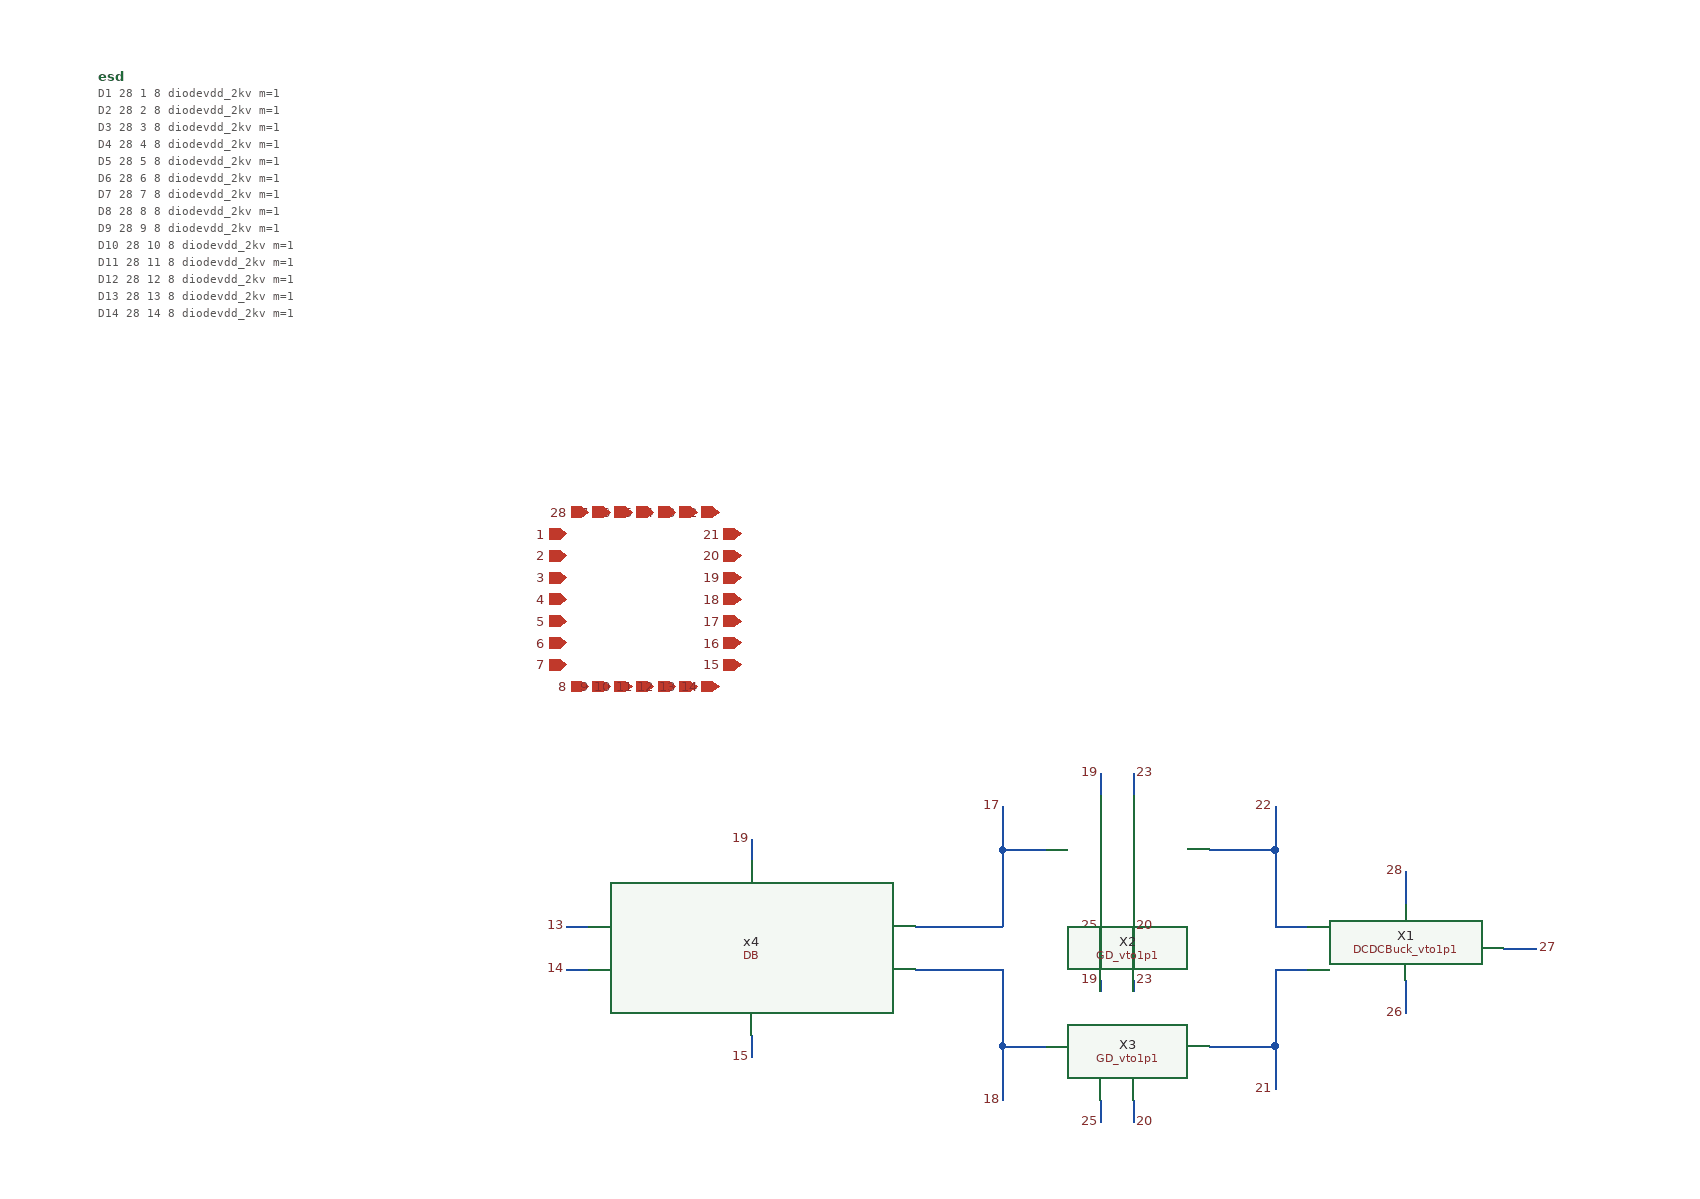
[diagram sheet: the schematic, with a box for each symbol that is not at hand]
v {xschem version=3.4.5 file_version=1.2
}
G {}
K {}
V {}
S {}
E {}
N -70 240 -70 260 {
lab=15}
N -70 60 -70 80 {
lab=19}
N 80 140 160 140 {
lab=17}
N 80 180 160 180 {
lab=18}
N -240 140 -220 140 {
lab=13}
N -240 180 -220 180 {
lab=14}
N 410 30 410 70 {
lab=22}
N 410 250 410 290 {
lab=21}
N 350 70 410 70 {
lab=22}
N 350 250 410 250 {
lab=21}
N 410 140 440 140 {
lab=22}
N 410 70 410 140 {
lab=22}
N 410 180 440 180 {
lab=21}
N 410 180 410 250 {
lab=21}
N 250 300 250 320 {
lab=25}
N 250 120 250 140 {
lab=25}
N 530 90 530 120 {
lab=28}
N 620 160 650 160 {
lab=27}
N 530 190 530 220 {
lab=26}
N 160 180 160 250 {
lab=18}
N 160 70 160 140 {
lab=17}
N 160 70 200 70 {
lab=17}
N 160 250 200 250 {
lab=18}
N 280 190 280 200 {
lab=23}
N 280 300 280 320 {
lab=20}
N 280 120 280 140 {
lab=20}
N 250 190 250 200 {
lab=19}
N 250 0 250 20 {
lab=19}
N 280 0 280 20 {
lab=23}
N 160 30 160 70 {
lab=17}
N 160 250 160 300 {
lab=18}
C {iopin.sym} -240 -220 2 0 {name=p8 lab=1}
C {iopin.sym} -240 -200 2 0 {name=p9 lab=2}
C {iopin.sym} -240 -180 2 0 {name=p10 lab=3}
C {iopin.sym} -240 -160 2 0 {name=p11 lab=4}
C {iopin.sym} -240 -140 2 0 {name=p12 lab=5}
C {iopin.sym} -240 -120 2 0 {name=p13 lab=6}
C {iopin.sym} -240 -100 2 0 {name=p14 lab=7}
C {iopin.sym} -220 -80 1 0 {name=p15 lab=8}
C {iopin.sym} -200 -80 1 0 {name=p16 lab=9}
C {iopin.sym} -180 -80 1 0 {name=p17 lab=10}
C {iopin.sym} -160 -80 1 0 {name=p18 lab=11}
C {iopin.sym} -140 -80 1 0 {name=p19 lab=12}
C {iopin.sym} -120 -80 1 0 {name=p20 lab=13}
C {iopin.sym} -100 -80 1 0 {name=p21 lab=14}
C {iopin.sym} -80 -100 0 0 {name=p22 lab=15}
C {iopin.sym} -80 -120 0 0 {name=p23 lab=16}
C {iopin.sym} -80 -140 0 0 {name=p24 lab=17}
C {iopin.sym} -80 -160 0 0 {name=p25 lab=18}
C {iopin.sym} -80 -180 0 0 {name=p26 lab=19}
C {iopin.sym} -80 -200 0 0 {name=p27 lab=20}
C {iopin.sym} -80 -220 0 0 {name=p28 lab=21}
C {iopin.sym} -100 -240 3 0 {name=p29 lab=22}
C {iopin.sym} -120 -240 3 0 {name=p30 lab=23}
C {iopin.sym} -140 -240 3 0 {name=p31 lab=24}
C {iopin.sym} -160 -240 3 0 {name=p32 lab=25}
C {iopin.sym} -180 -240 3 0 {name=p33 lab=26}
C {iopin.sym} -200 -240 3 0 {name=p34 lab=27}
C {iopin.sym} -220 -240 3 0 {name=p35 lab=28}
C {lab_pin.sym} -70 60 1 0 {name=p3 sig_type=std_logic lab=19}
C {code_shown.sym} -670 -640 0 0 {name=esd only_toplevel=false spice_ignore=true value="
D1 28 1 8 diodevdd_2kv m=1
D2 28 2 8 diodevdd_2kv m=1
D3 28 3 8 diodevdd_2kv m=1
D4 28 4 8 diodevdd_2kv m=1
D5 28 5 8 diodevdd_2kv m=1
D6 28 6 8 diodevdd_2kv m=1
D7 28 7 8 diodevdd_2kv m=1
D8 28 8 8 diodevdd_2kv m=1
D9 28 9 8 diodevdd_2kv m=1
D10 28 10 8 diodevdd_2kv m=1
D11 28 11 8 diodevdd_2kv m=1
D12 28 12 8 diodevdd_2kv m=1
D13 28 13 8 diodevdd_2kv m=1
D14 28 14 8 diodevdd_2kv m=1
D15 28 15 8 diodevdd_2kv m=1
D16 28 16 8 diodevdd_2kv m=1
D17 28 17 8 diodevdd_2kv m=1
D18 28 18 8 diodevdd_2kv m=1
D19 28 19 8 diodevdd_2kv m=1
D20 28 20 8 diodevdd_2kv m=1
D21 28 21 8 diodevdd_2kv m=1
D22 28 22 8 diodevdd_2kv m=1
D23 28 23 8 diodevdd_2kv m=1
D24 28 24 8 diodevdd_2kv m=1
D25 28 25 8 diodevdd_2kv m=1
D26 28 26 8 diodevdd_2kv m=1
D27 28 27 8 diodevdd_2kv m=1
D28 28 28 8 diodevdd_2kv m=1

D29 28 1 8 diodevss_2kv m=1
D30 28 2 8 diodevss_2kv m=1
D31 28 3 8 diodevss_2kv m=1
D32 28 4 8 diodevss_2kv m=1
D33 28 5 8 diodevss_2kv m=1
D34 28 6 8 diodevss_2kv m=1
D35 28 7 8 diodevss_2kv m=1
D36 28 8 8 diodevss_2kv m=1
D37 28 9 8 diodevss_2kv m=1
D38 28 10 8 diodevss_2kv m=1
D39 28 11 8 diodevss_2kv m=1
D40 28 12 8 diodevss_2kv m=1
D41 28 13 8 diodevss_2kv m=1
D42 28 14 8 diodevss_2kv m=1
D43 28 15 8 diodevss_2kv m=1
D44 28 16 8 diodevss_2kv m=1
D45 28 17 8 diodevss_2kv m=1
D46 28 18 8 diodevss_2kv m=1
D47 28 19 8 diodevss_2kv m=1
D48 28 20 8 diodevss_2kv m=1
D49 28 21 8 diodevss_2kv m=1
D50 28 22 8 diodevss_2kv m=1
D51 28 23 8 diodevss_2kv m=1
D52 28 24 8 diodevss_2kv m=1
D53 28 25 8 diodevss_2kv m=1
D54 28 26 8 diodevss_2kv m=1
D55 28 27 8 diodevss_2kv m=1
D56 28 28 8 diodevss_2kv m=1
"}
C {lab_pin.sym} -240 140 0 0 {name=p38 sig_type=std_logic lab=13}
C {lab_pin.sym} -240 180 0 0 {name=p39 sig_type=std_logic lab=14}
C {lab_pin.sym} -70 260 3 0 {name=p1 sig_type=std_logic lab=15}
C {lab_pin.sym} 410 30 0 0 {name=p2 sig_type=std_logic lab=22}
C {lab_pin.sym} 410 290 0 0 {name=p4 sig_type=std_logic lab=21}
C {lab_pin.sym} 250 320 0 0 {name=p5 sig_type=std_logic lab=25}
C {lab_pin.sym} 280 0 2 0 {name=p6 sig_type=std_logic lab=23}
C {lab_pin.sym} 280 190 2 0 {name=p7 sig_type=std_logic lab=23
}
C {lab_pin.sym} 530 90 0 0 {name=p36 sig_type=std_logic lab=28}
C {lab_pin.sym} 530 220 0 0 {name=p37 sig_type=std_logic lab=26}
C {lab_pin.sym} 250 140 0 0 {name=p40 sig_type=std_logic lab=25}
C {lab_pin.sym} 650 160 2 0 {name=p41 sig_type=std_logic lab=27}
C {../Digital_Block/DB.sym} -70 160 0 0 {name=x4}
C {../GD/GD_vto1p1.sym} 230 110 0 0 {name=X2}
C {../GD/GD_vto1p1.sym} 230 290 0 0 {name=X3}
C {../DCDCBuck/DCDCBuck_vto1p1.sym} 540 180 0 0 {name=X1}
C {lab_pin.sym} 280 140 0 1 {name=p42 sig_type=std_logic lab=20
}
C {lab_pin.sym} 280 320 0 1 {name=p43 sig_type=std_logic lab=20}
C {lab_pin.sym} 250 190 0 0 {name=p44 sig_type=std_logic lab=19}
C {lab_pin.sym} 250 0 0 0 {name=p45 sig_type=std_logic lab=19}
C {lab_pin.sym} 160 30 0 0 {name=p46 sig_type=std_logic lab=17
}
C {lab_pin.sym} 160 300 0 0 {name=p47 sig_type=std_logic lab=18
}
